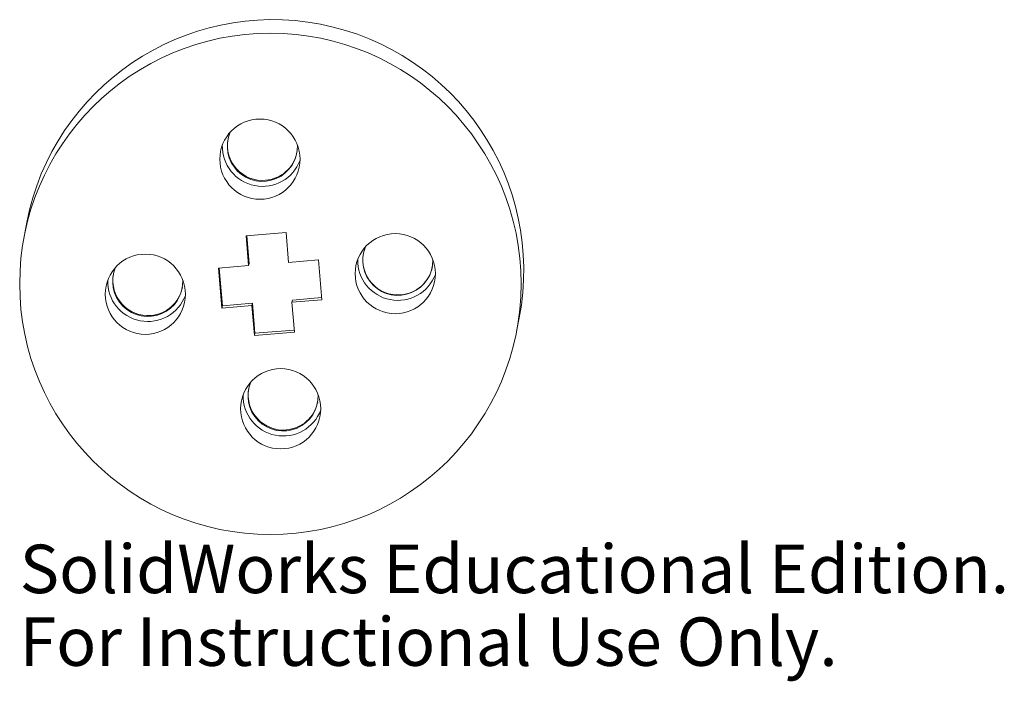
# Model space of a CAD drawing. Units: millimetres. Extents: x -25 to 73.2, y -39.6 to 26.4.
import ezdxf

# ---------------------------------------------------------------- set-up
doc = ezdxf.new("R2010")
doc.units = ezdxf.units.MM
doc.styles.add('SLDTEXTSTYLE0', font='TXT', dxfattribs={"width": 0.7})

msp = doc.modelspace()

# ---------------------------------------------------------------- linework, layer by layer
at = {"color": 7, "linetype": 'Continuous', "lineweight": 15}
for p, q in [((-24.279, 6.122), (-24.545, 4.746)), ((1.58, 5.142), (-2.406, 4.814)), ((1.828, 2.155), (1.58, 5.142)), ((-2.406, 4.814), (-2.158, 1.827)), ((-2.343, 4.819), (-2.114, 2.056)), ((-2.158, 1.827), (-2.114, 2.056)), ((4.818, 2.402), (1.828, 2.155)), ((5.148, -1.581), (4.818, 2.402)), ((-2.158, 1.827), (-5.148, 1.581)), ((-5.148, 1.581), (-4.818, -2.402)), ((-5.085, 1.586), (-4.773, -2.172)), ((-4.773, -2.172), (-1.784, -1.926)), ((-1.784, -1.926), (-1.828, -2.155)), ((-1.784, -1.926), (-1.536, -4.913)), ((2.158, -1.827), (5.148, -1.581)), ((2.158, -1.827), (2.203, -1.598)), ((2.406, -4.814), (2.158, -1.827)), ((2.203, -1.598), (5.129, -1.356)), ((-4.818, -2.402), (-1.828, -2.155)), ((-4.773, -2.172), (-4.818, -2.402)), ((-1.828, -2.155), (-1.58, -5.142)), ((24.545, -4.746), (24.811, -3.37)), ((-1.58, -5.142), (2.406, -4.814)), ((-1.536, -4.913), (2.388, -4.589)), ((-1.536, -4.913), (-1.58, -5.142))]:
    msp.add_line(p, q, dxfattribs=at)
for centre, radius in [((0.014, 0.017), 24.99), ((-1.031, 12.447), 3.999), ((12.459, 1.029), 3.999), ((-12.455, -1.024), 3.999), ((1.034, -12.442), 3.999)]:
    msp.add_circle(centre, radius, dxfattribs=at)
for centre, radius, start, end in [((0.262, 1.355), 25, 349.10619, 169.00648), ((-0.784, 13.731), 3.499, 156.27201, 1.84067), ((-0.783, 13.733), 4.001, 178.52811, 339.58457), ((-0.767, 13.823), 3.499, 169.86184, 274.74693), ((-0.763, 13.821), 3.497, 274.68821, 348.26873), ((12.715, 2.363), 3.499, 157.60935, 0.50333), ((12.722, 2.405), 3.499, 169.09606, 274.74729), ((12.716, 2.365), 4.001, 178.90175, 339.21092), ((-12.208, 0.26), 3.499, 156.27201, 1.84067), ((12.726, 2.403), 3.497, 274.68801, 349.0348), ((-12.208, 0.262), 4.001, 178.52811, 339.58457), ((-12.191, 0.352), 3.499, 169.86184, 274.74693), ((-12.187, 0.35), 3.497, 274.68821, 348.26873), ((1.281, -11.158), 3.499, 156.27201, 1.84067), ((1.298, -11.066), 3.499, 169.86184, 274.74693), ((1.282, -11.156), 4.001, 178.52811, 339.58457), ((1.302, -11.068), 3.497, 274.68821, 348.26873)]:
    msp.add_arc(centre, radius, start, end, dxfattribs=at)

# ---------------------------------------------------------------- texts
at = {"color": 7, "linetype": 'Continuous', "char_height": 4.83362, "attachment_point": 1, "style": 'SLDTEXTSTYLE0'}
for s, insert in [('SolidWorks Educational Edition.', (-24.977, -25.993)), ('For Instructional Use Only.', (-24.977, -33.244))]:
    msp.add_mtext(s, dxfattribs=dict(at, insert=insert))

doc.saveas('drawing.dxf')
